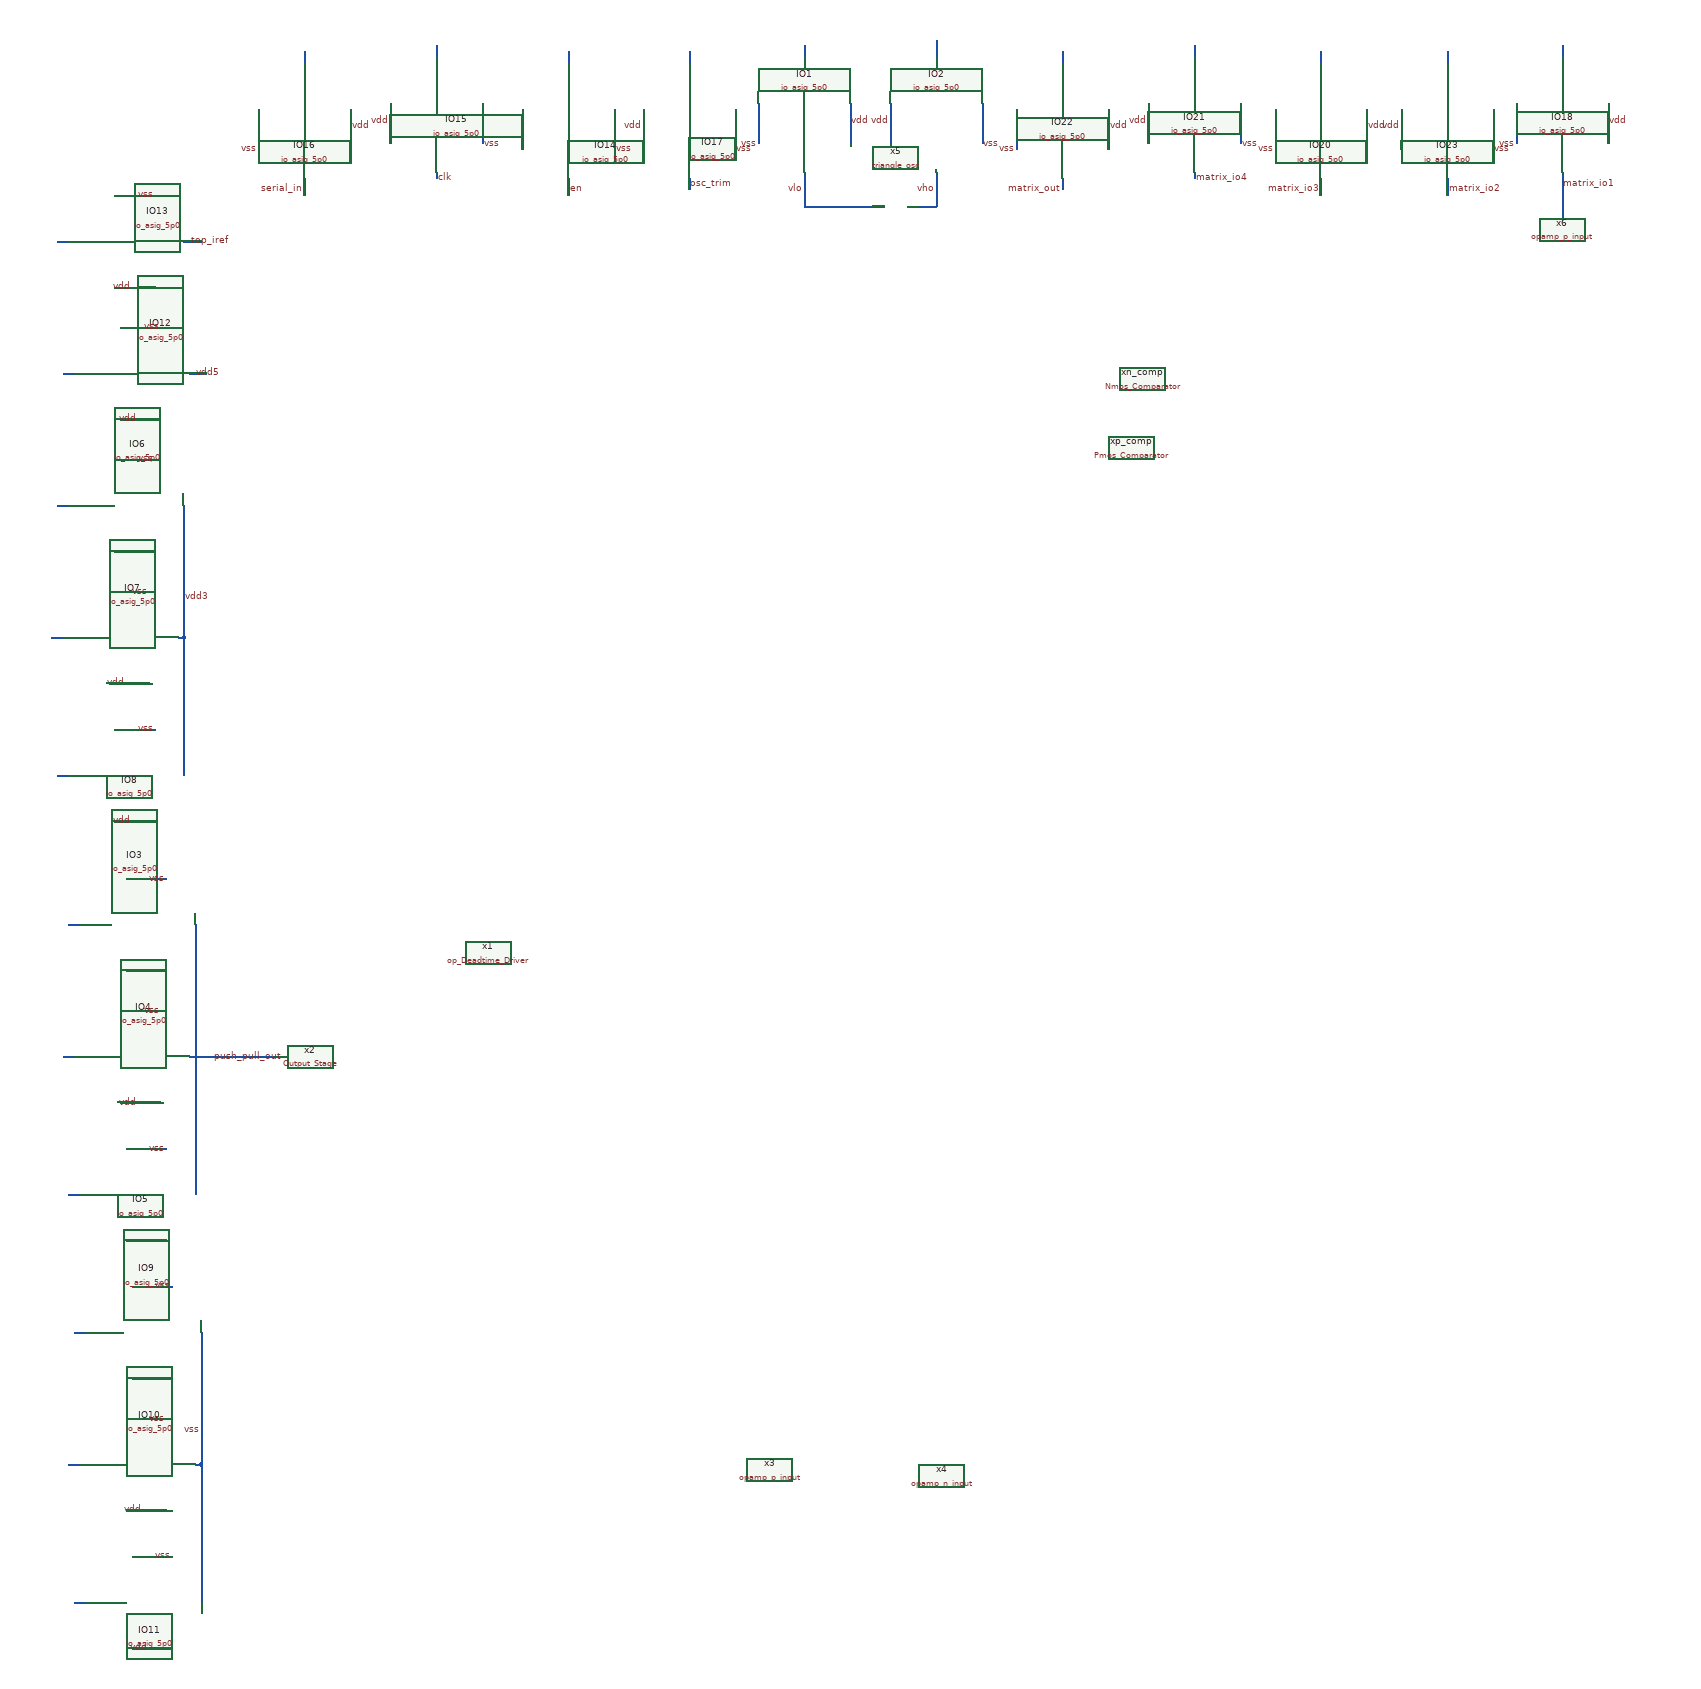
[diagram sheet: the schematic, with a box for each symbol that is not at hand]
v {xschem version=3.4.7 file_version=1.2}
G {}
K {}
V {}
S {}
E {}
N 1700 -2800 1750 -2800 {lab=vho}
N 1750 -2860 1750 -2800 {lab=vho}
N 1520 -2860 1520 -2800 {lab=vlo}
N 1440 -2980 1440 -2940 {lab=vss}
N 1670 -2980 1670 -2940 {lab=vdd}
N 1830 -2980 1830 -2940 {lab=vss}
N 1830 -2940 1830 -2910 {lab=vss}
N 1670 -2940 1670 -2910 {lab=vdd}
N 1600 -2980 1600 -2910 {lab=vdd}
N 1440 -2940 1440 -2910 {lab=vss}
N 1750 -3090 1750 -3060 {lab=#net1}
N 1520 -3080 1520 -3060 {lab=#net2}
N 340 -1630 380 -1630 {lab=vss}
N 340 -1470 410 -1470 {lab=vdd}
N 380 -1630 410 -1630 {lab=vss}
N 240 -1550 260 -1550 {lab=#net3}
N 330 -1400 370 -1400 {lab=vss}
N 330 -1240 400 -1240 {lab=vdd}
N 370 -1400 400 -1400 {lab=vss}
N 230 -1320 250 -1320 {lab=#net4}
N 340 -1160 380 -1160 {lab=vss}
N 340 -1000 410 -1000 {lab=vdd}
N 380 -1160 410 -1160 {lab=vss}
N 240 -1080 260 -1080 {lab=#net5}
N 450 -1320 600 -1320 {lab=push_pull_out}
N 460 -1550 460 -1320 {lab=push_pull_out}
N 460 -1320 460 -1080 {lab=push_pull_out}
N 320 -2360 360 -2360 {lab=vss}
N 320 -2200 390 -2200 {lab=vdd}
N 360 -2360 390 -2360 {lab=vss}
N 220 -2280 240 -2280 {lab=#net6}
N 310 -2130 350 -2130 {lab=vss}
N 310 -1970 380 -1970 {lab=vdd}
N 350 -2130 380 -2130 {lab=vss}
N 210 -2050 230 -2050 {lab=#net7}
N 320 -1890 360 -1890 {lab=vss}
N 320 -1730 390 -1730 {lab=vdd}
N 360 -1890 390 -1890 {lab=vss}
N 220 -1810 240 -1810 {lab=#net8}
N 440 -2280 440 -2050 {lab=vdd3}
N 440 -2050 440 -1810 {lab=vdd3}
N 350 -920 390 -920 {lab=vss}
N 350 -760 420 -760 {lab=vdd}
N 390 -920 420 -920 {lab=vss}
N 250 -840 270 -840 {lab=#net9}
N 340 -690 380 -690 {lab=vss}
N 340 -530 410 -530 {lab=vdd}
N 380 -690 410 -690 {lab=vss}
N 240 -610 260 -610 {lab=#net10}
N 350 -450 390 -450 {lab=vss}
N 350 -290 420 -290 {lab=vdd}
N 390 -450 420 -450 {lab=vss}
N 250 -370 270 -370 {lab=#net11}
N 470 -840 470 -610 {lab=vss}
N 470 -610 470 -370 {lab=vss}
N 460 -610 470 -610 {lab=vss}
N 430 -2050 440 -2050 {lab=vdd3}
N 330 -2590 370 -2590 {lab=vss}
N 330 -2430 400 -2430 {lab=vdd}
N 370 -2590 400 -2590 {lab=vss}
N 230 -2510 250 -2510 {lab=#net12}
N 320 -2820 360 -2820 {lab=vss}
N 320 -2660 390 -2660 {lab=vdd}
N 360 -2820 390 -2820 {lab=vss}
N 220 -2740 240 -2740 {lab=#net13}
N 440 -2740 470 -2740 {lab=top_iref}
N 450 -2510 480 -2510 {lab=vdd5}
N 1190 -2970 1190 -2930 {lab=vss}
N 1030 -2970 1030 -2900 {lab=vdd}
N 1190 -2930 1190 -2900 {lab=vss}
N 1110 -3070 1110 -3050 {lab=#net14}
N 960 -2980 960 -2940 {lab=vss}
N 800 -2980 800 -2910 {lab=vdd}
N 960 -2940 960 -2910 {lab=vss}
N 880 -3080 880 -3060 {lab=#net15}
N 570 -2970 570 -2930 {lab=vss}
N 730 -2970 730 -2900 {lab=vdd}
N 570 -2930 570 -2900 {lab=vss}
N 650 -3070 650 -3050 {lab=#net16}
N 880 -2860 880 -2850 {lab=clk}
N 650 -2850 650 -2820 {lab=serial_in}
N 1110 -2850 1110 -2820 {lab=en}
N 1520 -2800 1660 -2800 {lab=vlo}
N 1400 -2970 1400 -2930 {lab=vss}
N 1240 -2970 1240 -2900 {lab=vdd}
N 1400 -2930 1400 -2900 {lab=vss}
N 1320 -3070 1320 -3050 {lab=#net17}
N 1320 -2850 1320 -2830 {lab=osc_trim}
N 2760 -2980 2760 -2940 {lab=vss}
N 2920 -2980 2920 -2910 {lab=vdd}
N 2760 -2940 2760 -2910 {lab=vss}
N 2840 -3080 2840 -3060 {lab=#net18}
N 2340 -2970 2340 -2930 {lab=vss}
N 2500 -2970 2500 -2900 {lab=vdd}
N 2340 -2930 2340 -2900 {lab=vss}
N 2420 -3070 2420 -3050 {lab=#net19}
N 2280 -2980 2280 -2940 {lab=vss}
N 2120 -2980 2120 -2910 {lab=vdd}
N 2280 -2940 2280 -2910 {lab=vss}
N 2200 -3080 2200 -3060 {lab=#net20}
N 1890 -2970 1890 -2930 {lab=vss}
N 2050 -2970 2050 -2900 {lab=vdd}
N 1890 -2930 1890 -2900 {lab=vss}
N 1970 -3070 1970 -3050 {lab=#net21}
N 2200 -2860 2200 -2850 {lab=matrix_io4}
N 2720 -2970 2720 -2930 {lab=vss}
N 2560 -2970 2560 -2900 {lab=vdd}
N 2720 -2930 2720 -2900 {lab=vss}
N 2640 -3070 2640 -3050 {lab=#net22}
N 1970 -2850 1970 -2830 {lab=matrix_out}
N 2420 -2850 2420 -2820 {lab=matrix_io3}
N 2640 -2850 2640 -2820 {lab=matrix_io2}
N 2840 -2860 2840 -2830 {lab=matrix_io1}
N 2840 -2830 2840 -2780 {lab=matrix_io1}
C {title.sym} 70 30 0 0 {name=l1 author="Christopher O Amankwaa"}
C {libs/core_analog/Comparator/Pmos_Comparator.sym} 2090 -2380 0 1 {name=xp_comp}
C {libs/core_analog/Comparator/Nmos_Comparator.sym} 2110 -2500 0 1 {name=xn_comp}
C {libs/core_analog/op_Deadtime_Driver/op_Deadtime_Driver.sym} 970 -1500 3 1 {name=x1}
C {libs/core_analog/Output_Stage/Output_Stage.sym} 680 -1320 0 1 {name=x2}
C {libs/core_analog/opamp/opamp_p_input.sym} 1460 -600 0 1 {name=x3}
C {libs/core_analog/opamp/opamp_n_input.sym} 1760 -590 0 1 {name=x4}
C {libs/core_analog/oscillator/triangle_osc.sym} 1740 -2780 1 0 {name=x5}
C {libs/core_analog/opamp/opamp_p_input.sym} 2930 -2550 1 1 {name=x6}
C {libs/core_analog/Chipathon2025_pads/xschem/symbols/io_asig_5p0.sym} 1440 -3060 1 0 {name=IO1
model=gf180mcu_fd_io__asig_5p0_extracted
spiceprefix=X
}
C {libs/core_analog/Chipathon2025_pads/xschem/symbols/io_asig_5p0.sym} 1830 -3060 3 1 {name=IO2
model=gf180mcu_fd_io__asig_5p0_extracted
spiceprefix=X
}
C {lab_wire.sym} 1440 -2910 0 0 {name=p1 sig_type=std_logic lab=vss}
C {lab_wire.sym} 1830 -2910 0 1 {name=p2 sig_type=std_logic lab=vss}
C {lab_wire.sym} 1670 -2950 0 0 {name=p3 sig_type=std_logic lab=vdd}
C {lab_wire.sym} 1600 -2950 0 1 {name=p4 sig_type=std_logic lab=vdd}
C {noconn.sym} 1750 -3090 3 1 {name=l2}
C {noconn.sym} 1520 -3080 1 0 {name=l3}
C {lab_wire.sym} 1750 -2830 0 0 {name=p5 sig_type=std_logic lab=vho}
C {lab_wire.sym} 1520 -2830 0 0 {name=p6 sig_type=std_logic lab=vlo}
C {libs/core_analog/Chipathon2025_pads/xschem/symbols/io_asig_5p0.sym} 260 -1630 2 1 {name=IO3
model=gf180mcu_fd_io__asig_5p0_extracted
spiceprefix=X
}
C {lab_wire.sym} 410 -1630 3 1 {name=p7 sig_type=std_logic lab=vss}
C {lab_wire.sym} 370 -1470 3 0 {name=p8 sig_type=std_logic lab=vdd}
C {noconn.sym} 240 -1550 2 1 {name=l4}
C {libs/core_analog/Chipathon2025_pads/xschem/symbols/io_asig_5p0.sym} 250 -1400 2 1 {name=IO4
model=gf180mcu_fd_io__asig_5p0_extracted
spiceprefix=X
}
C {lab_wire.sym} 400 -1400 3 1 {name=p9 sig_type=std_logic lab=vss}
C {lab_wire.sym} 360 -1240 3 0 {name=p10 sig_type=std_logic lab=vdd}
C {noconn.sym} 230 -1320 2 1 {name=l5}
C {libs/core_analog/Chipathon2025_pads/xschem/symbols/io_asig_5p0.sym} 260 -1160 2 1 {name=IO5
model=gf180mcu_fd_io__asig_5p0_extracted
spiceprefix=X
}
C {lab_wire.sym} 410 -1160 3 1 {name=p11 sig_type=std_logic lab=vss}
C {lab_wire.sym} 370 -1000 3 0 {name=p12 sig_type=std_logic lab=vdd}
C {noconn.sym} 240 -1080 2 1 {name=l6}
C {lab_wire.sym} 490 -1320 0 1 {name=p13 sig_type=std_logic lab=push_pull_out}
C {libs/core_analog/Chipathon2025_pads/xschem/symbols/io_asig_5p0.sym} 240 -2360 2 1 {name=IO6
model=gf180mcu_fd_io__asig_5p0_extracted
spiceprefix=X
}
C {lab_wire.sym} 390 -2360 3 1 {name=p14 sig_type=std_logic lab=vss}
C {lab_wire.sym} 350 -2200 3 0 {name=p15 sig_type=std_logic lab=vdd}
C {noconn.sym} 220 -2280 2 1 {name=l7}
C {libs/core_analog/Chipathon2025_pads/xschem/symbols/io_asig_5p0.sym} 230 -2130 2 1 {name=IO7
model=gf180mcu_fd_io__asig_5p0_extracted
spiceprefix=X
}
C {lab_wire.sym} 380 -2130 3 1 {name=p16 sig_type=std_logic lab=vss}
C {lab_wire.sym} 340 -1970 3 0 {name=p17 sig_type=std_logic lab=vdd}
C {noconn.sym} 210 -2050 2 1 {name=l8}
C {libs/core_analog/Chipathon2025_pads/xschem/symbols/io_asig_5p0.sym} 240 -1890 2 1 {name=IO8
model=gf180mcu_fd_io__asig_5p0_extracted
spiceprefix=X
}
C {lab_wire.sym} 390 -1890 3 1 {name=p18 sig_type=std_logic lab=vss}
C {lab_wire.sym} 350 -1730 3 0 {name=p19 sig_type=std_logic lab=vdd}
C {noconn.sym} 220 -1810 2 1 {name=l9}
C {lab_wire.sym} 440 -2120 0 1 {name=p20 sig_type=std_logic lab=vdd3}
C {libs/core_analog/Chipathon2025_pads/xschem/symbols/io_asig_5p0.sym} 270 -920 2 1 {name=IO9
model=gf180mcu_fd_io__asig_5p0_extracted
spiceprefix=X
}
C {lab_wire.sym} 420 -920 3 1 {name=p21 sig_type=std_logic lab=vss}
C {lab_wire.sym} 380 -760 3 0 {name=p22 sig_type=std_logic lab=vdd}
C {noconn.sym} 250 -840 2 1 {name=l10}
C {libs/core_analog/Chipathon2025_pads/xschem/symbols/io_asig_5p0.sym} 260 -690 2 1 {name=IO10
model=gf180mcu_fd_io__asig_5p0_extracted
spiceprefix=X
}
C {lab_wire.sym} 410 -690 3 1 {name=p23 sig_type=std_logic lab=vss}
C {lab_wire.sym} 370 -530 3 0 {name=p24 sig_type=std_logic lab=vdd}
C {noconn.sym} 240 -610 2 1 {name=l11}
C {libs/core_analog/Chipathon2025_pads/xschem/symbols/io_asig_5p0.sym} 270 -450 2 1 {name=IO11
model=gf180mcu_fd_io__asig_5p0_extracted
spiceprefix=X
}
C {lab_wire.sym} 420 -450 3 1 {name=p25 sig_type=std_logic lab=vss}
C {lab_wire.sym} 380 -290 3 0 {name=p26 sig_type=std_logic lab=vdd}
C {noconn.sym} 250 -370 2 1 {name=l12}
C {lab_wire.sym} 470 -670 3 1 {name=p27 sig_type=std_logic lab=vss}
C {libs/core_analog/Chipathon2025_pads/xschem/symbols/io_asig_5p0.sym} 250 -2590 2 1 {name=IO12
model=gf180mcu_fd_io__asig_5p0_extracted
spiceprefix=X
}
C {lab_wire.sym} 400 -2590 3 1 {name=p28 sig_type=std_logic lab=vss}
C {lab_wire.sym} 360 -2430 3 0 {name=p29 sig_type=std_logic lab=vdd}
C {noconn.sym} 230 -2510 2 1 {name=l13}
C {libs/core_analog/Chipathon2025_pads/xschem/symbols/io_asig_5p0.sym} 240 -2820 2 1 {name=IO13
model=gf180mcu_fd_io__asig_5p0_extracted
spiceprefix=X
}
C {lab_wire.sym} 390 -2820 3 1 {name=p30 sig_type=std_logic lab=vss}
C {lab_wire.sym} 350 -2660 3 0 {name=p31 sig_type=std_logic lab=vdd}
C {noconn.sym} 220 -2740 2 1 {name=l14}
C {lab_wire.sym} 460 -2510 0 1 {name=p32 sig_type=std_logic lab=vdd5}
C {lab_wire.sym} 450 -2740 0 1 {name=p33 sig_type=std_logic lab=top_iref}
C {libs/core_analog/Chipathon2025_pads/xschem/symbols/io_asig_5p0.sym} 1190 -3050 3 1 {name=IO14
model=gf180mcu_fd_io__asig_5p0_extracted
spiceprefix=X
}
C {lab_wire.sym} 1190 -2900 0 1 {name=p34 sig_type=std_logic lab=vss}
C {lab_wire.sym} 1030 -2940 0 0 {name=p35 sig_type=std_logic lab=vdd}
C {noconn.sym} 1110 -3070 3 1 {name=l15}
C {libs/core_analog/Chipathon2025_pads/xschem/symbols/io_asig_5p0.sym} 960 -3060 3 1 {name=IO15
model=gf180mcu_fd_io__asig_5p0_extracted
spiceprefix=X
}
C {lab_wire.sym} 960 -2910 0 1 {name=p36 sig_type=std_logic lab=vss}
C {lab_wire.sym} 800 -2950 0 0 {name=p37 sig_type=std_logic lab=vdd}
C {noconn.sym} 880 -3080 3 1 {name=l16}
C {libs/core_analog/Chipathon2025_pads/xschem/symbols/io_asig_5p0.sym} 570 -3050 1 0 {name=IO16
model=gf180mcu_fd_io__asig_5p0_extracted
spiceprefix=X
}
C {lab_wire.sym} 570 -2900 0 0 {name=p38 sig_type=std_logic lab=vss}
C {lab_wire.sym} 730 -2940 0 1 {name=p39 sig_type=std_logic lab=vdd}
C {noconn.sym} 650 -3070 1 0 {name=l17}
C {lab_wire.sym} 650 -2830 0 0 {name=p40 sig_type=std_logic lab=serial_in}
C {lab_wire.sym} 880 -2850 0 1 {name=p41 sig_type=std_logic lab=clk}
C {lab_wire.sym} 1110 -2830 0 1 {name=p42 sig_type=std_logic lab=en}
C {libs/core_analog/Chipathon2025_pads/xschem/symbols/io_asig_5p0.sym} 1400 -3050 3 1 {name=IO17
model=gf180mcu_fd_io__asig_5p0_extracted
spiceprefix=X
}
C {lab_wire.sym} 1400 -2900 0 1 {name=p43 sig_type=std_logic lab=vss}
C {lab_wire.sym} 1240 -2940 0 0 {name=p44 sig_type=std_logic lab=vdd}
C {noconn.sym} 1320 -3070 3 1 {name=l18}
C {lab_wire.sym} 1320 -2840 0 1 {name=p45 sig_type=std_logic lab=osc_trim}
C {libs/core_analog/Chipathon2025_pads/xschem/symbols/io_asig_5p0.sym} 2760 -3060 1 0 {name=IO18
model=gf180mcu_fd_io__asig_5p0_extracted
spiceprefix=X
}
C {lab_wire.sym} 2760 -2910 0 0 {name=p46 sig_type=std_logic lab=vss}
C {lab_wire.sym} 2920 -2950 0 1 {name=p49 sig_type=std_logic lab=vdd}
C {libs/core_analog/Chipathon2025_pads/xschem/symbols/io_asig_5p0.sym} 2340 -3050 1 0 {name=IO20
model=gf180mcu_fd_io__asig_5p0_extracted
spiceprefix=X
}
C {lab_wire.sym} 2340 -2900 0 0 {name=p50 sig_type=std_logic lab=vss}
C {lab_wire.sym} 2500 -2940 0 1 {name=p51 sig_type=std_logic lab=vdd}
C {noconn.sym} 2420 -3070 1 0 {name=l19}
C {libs/core_analog/Chipathon2025_pads/xschem/symbols/io_asig_5p0.sym} 2280 -3060 3 1 {name=IO21
model=gf180mcu_fd_io__asig_5p0_extracted
spiceprefix=X
}
C {lab_wire.sym} 2280 -2910 0 1 {name=p52 sig_type=std_logic lab=vss}
C {lab_wire.sym} 2120 -2950 0 0 {name=p53 sig_type=std_logic lab=vdd}
C {libs/core_analog/Chipathon2025_pads/xschem/symbols/io_asig_5p0.sym} 1890 -3050 1 0 {name=IO22
model=gf180mcu_fd_io__asig_5p0_extracted
spiceprefix=X
}
C {lab_wire.sym} 1890 -2900 0 0 {name=p54 sig_type=std_logic lab=vss}
C {lab_wire.sym} 2050 -2940 0 1 {name=p55 sig_type=std_logic lab=vdd}
C {noconn.sym} 1970 -3070 1 0 {name=l20}
C {lab_wire.sym} 2200 -2850 0 1 {name=p56 sig_type=std_logic lab=matrix_io4}
C {libs/core_analog/Chipathon2025_pads/xschem/symbols/io_asig_5p0.sym} 2720 -3050 3 1 {name=IO23
model=gf180mcu_fd_io__asig_5p0_extracted
spiceprefix=X
}
C {lab_wire.sym} 2720 -2900 0 1 {name=p57 sig_type=std_logic lab=vss}
C {lab_wire.sym} 2560 -2940 0 0 {name=p58 sig_type=std_logic lab=vdd}
C {noconn.sym} 2640 -3070 3 1 {name=l21}
C {lab_wire.sym} 1970 -2830 0 0 {name=p59 sig_type=std_logic lab=matrix_out}
C {lab_wire.sym} 2420 -2830 0 0 {name=p60 sig_type=std_logic lab=matrix_io3}
C {lab_wire.sym} 2640 -2830 0 1 {name=p61 sig_type=std_logic lab=matrix_io2}
C {lab_wire.sym} 2840 -2840 0 1 {name=p62 sig_type=std_logic lab=matrix_io1}
C {noconn.sym} 2840 -3080 3 1 {name=l22}
C {noconn.sym} 2200 -3080 3 1 {name=l23}
